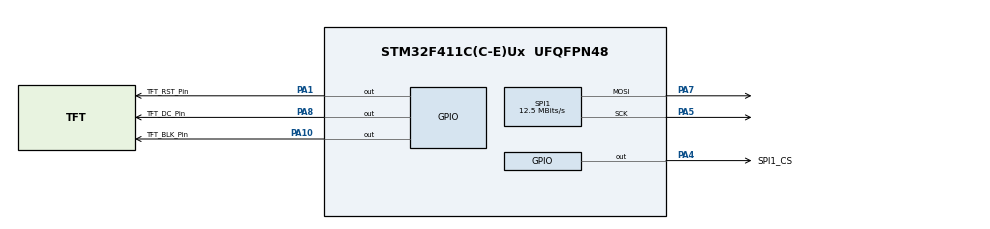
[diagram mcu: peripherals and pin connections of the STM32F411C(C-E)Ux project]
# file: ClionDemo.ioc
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Dma.Request0=SPI1_TX
Dma.SPI1_TX.0.Direction=DMA_MEMORY_TO_PERIPH
Dma.SPI1_TX.0.FIFOMode=DMA_FIFOMODE_DISABLE
Dma.SPI1_TX.0.Instance=DMA2_Stream3
Dma.SPI1_TX.0.MemDataAlignment=DMA_MDATAALIGN_BYTE
Dma.SPI1_TX.0.MemInc=DMA_MINC_ENABLE
Dma.SPI1_TX.0.Mode=DMA_NORMAL
Dma.SPI1_TX.0.PeriphDataAlignment=DMA_PDATAALIGN_BYTE
Dma.SPI1_TX.0.PeriphInc=DMA_PINC_DISABLE
Dma.SPI1_TX.0.Priority=DMA_PRIORITY_MEDIUM
Mcu.Family=STM32F4
Mcu.Name=STM32F411C(C-E)Ux
Mcu.Package=UFQFPN48
NVIC.DMA2_Stream3_IRQn=true\:8\:0\:true\:false\:true\:false\:true\:true
NVIC.PriorityGroup=NVIC_PRIORITYGROUP_4
PA1.GPIO_Label=TFT_RST_Pin
PA1.GPIO_PuPd=GPIO_PULLUP
PA1.PinState=GPIO_PIN_SET
PA1.Signal=GPIO_Output
PA10.GPIO_Label=TFT_BLK_Pin
PA10.PinState=GPIO_PIN_SET
PA10.Signal=GPIO_Output
PA13.Mode=Serial_Wire
PA13.Signal=SYS_JTMS-SWDIO
PA14.Mode=Serial_Wire
PA14.Signal=SYS_JTCK-SWCLK
PA4.GPIO_Label=SPI1_CS
PA4.GPIO_PuPd=GPIO_PULLUP
PA4.PinState=GPIO_PIN_SET
PA4.Signal=GPIO_Output
PA5.GPIO_PuPd=GPIO_PULLUP
PA5.Mode=TX_Only_Simplex_Unidirect_Master
PA5.Signal=SPI1_SCK
PA7.GPIO_PuPd=GPIO_PULLUP
PA7.Mode=TX_Only_Simplex_Unidirect_Master
PA7.Signal=SPI1_MOSI
PA8.GPIO_Label=TFT_DC_Pin
PA8.GPIO_PuPd=GPIO_PULLUP
PA8.PinState=GPIO_PIN_SET
PA8.Signal=GPIO_Output
PH0\ -\ OSC_IN.Mode=HSE-External-Oscillator
PH0\ -\ OSC_IN.Signal=RCC_OSC_IN
PH1\ -\ OSC_OUT.Mode=HSE-External-Oscillator
PH1\ -\ OSC_OUT.Signal=RCC_OSC_OUT
ProjectManager.HeapSize=0x800
ProjectManager.StackSize=0x800
ProjectManager.TargetToolchain=STM32CubeIDE
RCC.48MHZClocksFreq_Value=50000000
RCC.AHBFreq_Value=100000000
RCC.APB1CLKDivider=RCC_HCLK_DIV2
RCC.APB1Freq_Value=50000000
RCC.APB1TimFreq_Value=100000000
RCC.APB2Freq_Value=100000000
RCC.APB2TimFreq_Value=100000000
RCC.CortexFreq_Value=100000000
RCC.HCLKFreq_Value=100000000
RCC.HSE_VALUE=25000000
RCC.HSI_VALUE=16000000
RCC.LSE_VALUE=32768
RCC.PLLM=12
RCC.PLLN=96
RCC.PLLSourceVirtual=RCC_PLLSOURCE_HSE
RCC.SYSCLKFreq_VALUE=100000000
RCC.SYSCLKSource=RCC_SYSCLKSOURCE_PLLCLK
RCC.VCOOutputFreq_Value=200000000
SPI1.BaudRatePrescaler=SPI_BAUDRATEPRESCALER_8
SPI1.CLKPhase=SPI_PHASE_2EDGE
SPI1.CLKPolarity=SPI_POLARITY_HIGH
SPI1.CRCCalculation=SPI_CRCCALCULATION_DISABLE
SPI1.CalculateBaudRate=12.5 MBits/s
SPI1.Direction=SPI_DIRECTION_2LINES
SPI1.Mode=SPI_MODE_MASTER
SPI1.VirtualType=VM_MASTER
board=custom

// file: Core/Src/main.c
/* USER CODE BEGIN Header */
/**
  ******************************************************************************
  * @file           : main.c
  * @brief          : Main program body
  ******************************************************************************
  * @attention
  *
  * Copyright (c) 2022 STMicroelectronics.
  * All rights reserved.
  *
  * This software is licensed under terms that can be found in the LICENSE file
  * in the root directory of this software component.
  * If no LICENSE file comes with this software, it is provided AS-IS.
  *
  ******************************************************************************
  */
/* USER CODE END Header */
#include "main.h"
#include "dma.h"
#include "spi.h"
#include "gpio.h"

/* USER CODE BEGIN Includes */
#include "lcd.h"
#include "../../lvgl/src/core/lv_obj.h"
#include "../../lvgl/src/lv_api_map.h"
#include "lv_port_disp.h"
/* USER CODE END Includes */

void SystemClock_Config(void);

int main(void)
{

  /* MCU Configuration--------------------------------------------------------*/

  /* Reset of all peripherals, Initializes the Flash interface and the Systick. */
  HAL_Init();

  /* Configure the system clock */
  SystemClock_Config();

  /* Initialize all configured peripherals */
  MX_GPIO_Init();
  MX_DMA_Init();
  MX_SPI1_Init();
  /* USER CODE BEGIN 2 */
  LCD_Init();
  lv_init();
  lv_port_disp_init();
  /*屏幕显示红色*/
  lv_color_t bg_color = lv_color_make(0xF8,0x00,0x00);
  lv_obj_set_style_bg_color(lv_scr_act(),bg_color,0);

  /* USER CODE END 2 */

  /* Infinite loop */
  while (1)
  {

    /* USER CODE BEGIN 3 */
      HAL_Delay(3);
      lv_task_handler();
  }
  /* USER CODE END 3 */
}

void SystemClock_Config(void)
{
  RCC_OscInitTypeDef RCC_OscInitStruct = {0};
  RCC_ClkInitTypeDef RCC_ClkInitStruct = {0};

  /** Configure the main internal regulator output voltage
  */
  __HAL_RCC_PWR_CLK_ENABLE();
  __HAL_PWR_VOLTAGESCALING_CONFIG(PWR_REGULATOR_VOLTAGE_SCALE1);

    //先将时钟源选择为内部时钟
    RCC_ClkInitStruct.ClockType = RCC_CLOCKTYPE_SYSCLK;
    RCC_ClkInitStruct.SYSCLKSource = RCC_SYSCLKSOURCE_HSI;
    if (HAL_RCC_ClockConfig(&RCC_ClkInitStruct, FLASH_LATENCY_5) != HAL_OK)
    {
        Error_Handler();
    }
  /** Initializes the RCC Oscillators according to the specified parameters
  * in the RCC_OscInitTypeDef structure.
  */
  RCC_OscInitStruct.OscillatorType = RCC_OSCILLATORTYPE_HSE;
  RCC_OscInitStruct.HSEState = RCC_HSE_ON;
  RCC_OscInitStruct.PLL.PLLState = RCC_PLL_ON;
  RCC_OscInitStruct.PLL.PLLSource = RCC_PLLSOURCE_HSE;
  RCC_OscInitStruct.PLL.PLLM = 12;
  RCC_OscInitStruct.PLL.PLLN = 96;
  RCC_OscInitStruct.PLL.PLLP = RCC_PLLP_DIV2;
  RCC_OscInitStruct.PLL.PLLQ = 4;
  if (HAL_RCC_OscConfig(&RCC_OscInitStruct) != HAL_OK)
  {
    Error_Handler();
  }

  /** Initializes the CPU, AHB and APB buses clocks
  */
  RCC_ClkInitStruct.ClockType = RCC_CLOCKTYPE_HCLK|RCC_CLOCKTYPE_SYSCLK
                              |RCC_CLOCKTYPE_PCLK1|RCC_CLOCKTYPE_PCLK2;
  RCC_ClkInitStruct.SYSCLKSource = RCC_SYSCLKSOURCE_PLLCLK;
  RCC_ClkInitStruct.AHBCLKDivider = RCC_SYSCLK_DIV1;
  RCC_ClkInitStruct.APB1CLKDivider = RCC_HCLK_DIV2;
  RCC_ClkInitStruct.APB2CLKDivider = RCC_HCLK_DIV1;

  if (HAL_RCC_ClockConfig(&RCC_ClkInitStruct, FLASH_LATENCY_3) != HAL_OK)
  {
    Error_Handler();
  }
}

void Error_Handler(void)
{
  __disable_irq();
  while (1)
  {
  }
}
